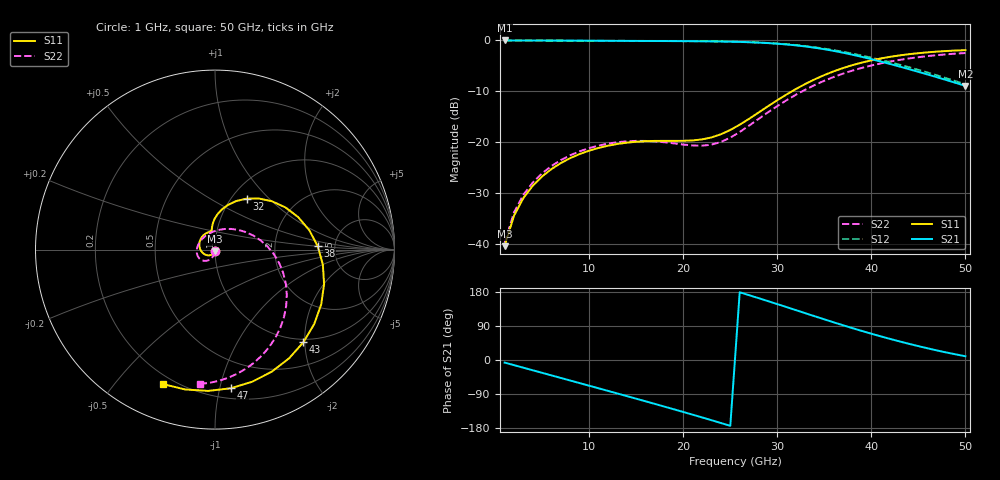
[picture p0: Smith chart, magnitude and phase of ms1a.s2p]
! Impedora 0.10.0 via model, case ms1a (fullwave/cases.json), 2026-11-19
! As ms1 with the antipad as large as the pad: no plane opening beyond the pad: with its pads and traces, ports at the far end of each trace, after the 3D port calibration.
! Ports: 1 = upper end, 2 = lower end, 50 ohm.
! Compared with the edge 3D mesh.
# Hz S RI R 50
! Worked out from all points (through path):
!   50 points, 1 GHz to 50 GHz, reference 50 ohm
!   highest |S21| = 0.00 dB at 1 GHz (marker M1); lowest = -8.9 dB at 50 GHz (marker M2)
!   group delay of S21, straight-line fit = 20.2 ps
!   lowest |S11| = -40.4 dB at 1 GHz (marker M3), VSWR 1.02, Z = 49.8 - j0.941 ohm
!   |S11| at or under -10 dB: start of sweep to 31.54 GHz
!   |S22| runs from -39.7 to -2.5 dB; largest |S21 - S12| = 1.3
!   S11 on the Smith chart (normalised r, x): 1 GHz: 1.00, -0.02; 32 GHz: 1.17, +0.75; 38 GHz: 3.67, +0.20; 43 GHz: 0.94, -1.97; 47 GHz: 0.28, -1.08; 50 GHz: 0.16, -0.67
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1e9  -0.00152 -0.00944  0.9929 -0.1182  0.9976 -0.0673  -0.000754 -0.0103
2e9  -0.006 -0.0181  0.9717 -0.2347  0.9906 -0.1342  -0.003 -0.0203
4e9  -0.0225 -0.0301  0.8885 -0.4557  0.9626 -0.2655  -0.0118 -0.0386
7e9  -0.0566 -0.027  0.673 -0.7346  0.8878 -0.4519  -0.0339 -0.0579
1e10  -0.0828 0.00253  0.3738 -0.9206  0.777 -0.6192  -0.0617 -0.0625
1.2e10  -0.0875 0.0306  0.1458 -0.981  0.6851 -0.7173  -0.0796 -0.0557
1.4e10  -0.0803 0.0582  -0.0908 -0.9858  0.5801 -0.8027  -0.0939 -0.0407
1.8e10  -0.0453 0.0929  -0.5377 -0.8271  0.3354 -0.9289  -0.0996 0.0102
2.2e10  -0.0204 0.1049  -0.8627 -0.4674  0.0531 -0.9815  -0.0559 0.0739
2.4e10  -0.0173 0.1187  -0.948 -0.2322  -0.0969 -0.9731  -0.00993 0.1003
2.6e10  -0.0113 0.1485  -0.9669 0.0216  -0.2476 -0.9369  0.0526 0.1148
2.9e10  0.0371 0.2226  -0.8567 0.3918  -0.4596 -0.825  0.1706 0.0979
3.2e10  0.1767 0.2841  -0.5917 0.671  -0.6256 -0.6465  0.2935 0.0163
3.4e10  0.3175 0.2693  -0.362 0.7667  -0.6941 -0.5018  0.3581 -0.0759
3.6e10  0.4638 0.1808  -0.1286 0.7794  -0.7223 -0.3514  0.3946 -0.1906
3.8e10  0.5726 0.0184  0.0759 0.7202  -0.7122 -0.2095  0.3965 -0.315
4e10  0.6078 -0.193  0.2311 0.6131  -0.6716 -0.0873  0.3639 -0.4356
4.2e10  0.5531 -0.414  0.3319 0.4844  -0.611 0.00958  0.3025 -0.5421
4.3e10  0.4929 -0.5155  0.3635 0.4185  -0.5763 0.0481  0.2635 -0.5879
4.5e10  0.3168 -0.6799  0.395 0.2934  -0.5035 0.106  0.1735 -0.6626
4.7e10  0.0874 -0.7726  0.3936 0.1845  -0.4315 0.141  0.0736 -0.714
5e10  -0.2918 -0.7488  0.3528 0.0618  -0.3354 0.158  -0.0818 -0.7481
